VERSION 5.7 ;
  NOWIREEXTENSIONATPIN ON ;
  DIVIDERCHAR "/" ;
  BUSBITCHARS "[]" ;
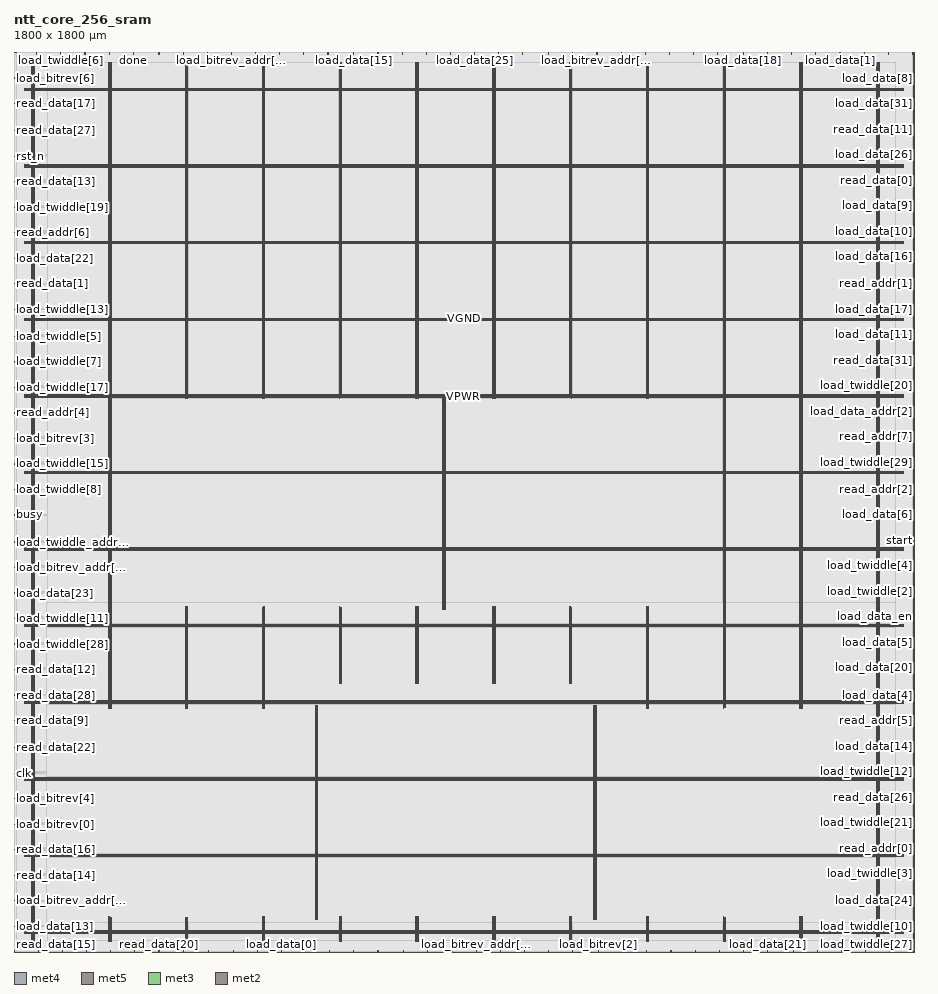
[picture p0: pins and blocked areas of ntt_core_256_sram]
MACRO ntt_core_256_sram
  CLASS BLOCK ;
  FOREIGN ntt_core_256_sram ;
  ORIGIN 0.000 0.000 ;
  SIZE 1800.000 BY 1800.000 ;
  PIN VGND
    DIRECTION INOUT ;
    USE GROUND ;
    PORT
      LAYER met4 ;
        RECT 39.060 21.520 40.660 1779.120 ;
    END
    PORT
      LAYER met4 ;
        RECT 192.660 21.520 194.260 69.400 ;
    END
    PORT
      LAYER met4 ;
        RECT 192.660 487.480 194.260 1779.120 ;
    END
    PORT
      LAYER met4 ;
        RECT 346.260 21.520 347.860 69.400 ;
    END
    PORT
      LAYER met4 ;
        RECT 346.260 487.480 347.860 690.020 ;
    END
    PORT
      LAYER met4 ;
        RECT 346.260 1107.480 347.860 1779.120 ;
    END
    PORT
      LAYER met4 ;
        RECT 499.860 21.520 501.460 70.020 ;
    END
    PORT
      LAYER met4 ;
        RECT 499.860 487.480 501.460 690.020 ;
    END
    PORT
      LAYER met4 ;
        RECT 499.860 1107.480 501.460 1779.120 ;
    END
    PORT
      LAYER met4 ;
        RECT 653.460 21.520 655.060 70.020 ;
    END
    PORT
      LAYER met4 ;
        RECT 653.460 536.440 655.060 689.400 ;
    END
    PORT
      LAYER met4 ;
        RECT 653.460 1108.100 655.060 1779.120 ;
    END
    PORT
      LAYER met4 ;
        RECT 807.060 21.520 808.660 70.020 ;
    END
    PORT
      LAYER met4 ;
        RECT 807.060 536.440 808.660 690.020 ;
    END
    PORT
      LAYER met4 ;
        RECT 807.060 1107.480 808.660 1779.120 ;
    END
    PORT
      LAYER met4 ;
        RECT 960.660 21.520 962.260 70.020 ;
    END
    PORT
      LAYER met4 ;
        RECT 960.660 536.440 962.260 690.020 ;
    END
    PORT
      LAYER met4 ;
        RECT 960.660 1107.480 962.260 1779.120 ;
    END
    PORT
      LAYER met4 ;
        RECT 1114.260 21.520 1115.860 70.020 ;
    END
    PORT
      LAYER met4 ;
        RECT 1114.260 536.440 1115.860 689.400 ;
    END
    PORT
      LAYER met4 ;
        RECT 1114.260 1107.480 1115.860 1779.120 ;
    END
    PORT
      LAYER met4 ;
        RECT 1267.860 21.520 1269.460 70.020 ;
    END
    PORT
      LAYER met4 ;
        RECT 1267.860 487.480 1269.460 690.020 ;
    END
    PORT
      LAYER met4 ;
        RECT 1267.860 1107.480 1269.460 1779.120 ;
    END
    PORT
      LAYER met4 ;
        RECT 1421.460 21.520 1423.060 69.400 ;
    END
    PORT
      LAYER met4 ;
        RECT 1421.460 488.100 1423.060 1779.120 ;
    END
    PORT
      LAYER met4 ;
        RECT 1575.060 21.520 1576.660 70.020 ;
    END
    PORT
      LAYER met4 ;
        RECT 1575.060 487.480 1576.660 1779.120 ;
    END
    PORT
      LAYER met4 ;
        RECT 1728.660 21.520 1730.260 1779.120 ;
    END
    PORT
      LAYER met5 ;
        RECT 20.000 40.910 1779.980 42.510 ;
    END
    PORT
      LAYER met5 ;
        RECT 20.000 194.090 1779.980 195.690 ;
    END
    PORT
      LAYER met5 ;
        RECT 20.000 347.270 1779.980 348.870 ;
    END
    PORT
      LAYER met5 ;
        RECT 20.000 500.450 1779.980 502.050 ;
    END
    PORT
      LAYER met5 ;
        RECT 20.000 653.630 1779.980 655.230 ;
    END
    PORT
      LAYER met5 ;
        RECT 20.000 806.810 1779.980 808.410 ;
    END
    PORT
      LAYER met5 ;
        RECT 20.000 959.990 1779.980 961.590 ;
    END
    PORT
      LAYER met5 ;
        RECT 20.000 1113.170 1779.980 1114.770 ;
    END
    PORT
      LAYER met5 ;
        RECT 20.000 1266.350 1779.980 1267.950 ;
    END
    PORT
      LAYER met5 ;
        RECT 20.000 1419.530 1779.980 1421.130 ;
    END
    PORT
      LAYER met5 ;
        RECT 20.000 1572.710 1779.980 1574.310 ;
    END
    PORT
      LAYER met5 ;
        RECT 20.000 1725.890 1779.980 1727.490 ;
    END
    PORT
      LAYER met4 ;
        RECT 605.940 65.040 607.540 492.560 ;
    END
    PORT
      LAYER met4 ;
        RECT 860.780 685.200 862.380 1112.720 ;
    END
    PORT
      LAYER met4 ;
        RECT 1163.460 65.040 1165.060 492.560 ;
    END
  END VGND
  PIN VPWR
    DIRECTION INOUT ;
    USE POWER ;
    PORT
      LAYER met4 ;
        RECT 35.760 21.520 37.360 1779.120 ;
    END
    PORT
      LAYER met4 ;
        RECT 189.360 21.520 190.960 70.020 ;
    END
    PORT
      LAYER met4 ;
        RECT 189.360 487.480 190.960 1779.120 ;
    END
    PORT
      LAYER met4 ;
        RECT 342.960 21.520 344.560 69.400 ;
    END
    PORT
      LAYER met4 ;
        RECT 342.960 487.480 344.560 690.020 ;
    END
    PORT
      LAYER met4 ;
        RECT 342.960 1107.480 344.560 1779.120 ;
    END
    PORT
      LAYER met4 ;
        RECT 496.560 21.520 498.160 70.020 ;
    END
    PORT
      LAYER met4 ;
        RECT 496.560 487.480 498.160 689.400 ;
    END
    PORT
      LAYER met4 ;
        RECT 496.560 1107.480 498.160 1779.120 ;
    END
    PORT
      LAYER met4 ;
        RECT 650.160 21.520 651.760 70.020 ;
    END
    PORT
      LAYER met4 ;
        RECT 650.160 536.440 651.760 690.020 ;
    END
    PORT
      LAYER met4 ;
        RECT 650.160 1107.480 651.760 1779.120 ;
    END
    PORT
      LAYER met4 ;
        RECT 803.760 21.520 805.360 70.020 ;
    END
    PORT
      LAYER met4 ;
        RECT 803.760 537.060 805.360 690.020 ;
    END
    PORT
      LAYER met4 ;
        RECT 803.760 1107.480 805.360 1779.120 ;
    END
    PORT
      LAYER met4 ;
        RECT 957.360 21.520 958.960 70.020 ;
    END
    PORT
      LAYER met4 ;
        RECT 957.360 536.440 958.960 690.020 ;
    END
    PORT
      LAYER met4 ;
        RECT 957.360 1107.480 958.960 1779.120 ;
    END
    PORT
      LAYER met4 ;
        RECT 1110.960 21.520 1112.560 70.020 ;
    END
    PORT
      LAYER met4 ;
        RECT 1110.960 536.440 1112.560 690.020 ;
    END
    PORT
      LAYER met4 ;
        RECT 1110.960 1108.100 1112.560 1779.120 ;
    END
    PORT
      LAYER met4 ;
        RECT 1264.560 21.520 1266.160 70.020 ;
    END
    PORT
      LAYER met4 ;
        RECT 1264.560 487.480 1266.160 690.020 ;
    END
    PORT
      LAYER met4 ;
        RECT 1264.560 1107.480 1266.160 1779.120 ;
    END
    PORT
      LAYER met4 ;
        RECT 1418.160 21.520 1419.760 70.020 ;
    END
    PORT
      LAYER met4 ;
        RECT 1418.160 487.480 1419.760 1779.120 ;
    END
    PORT
      LAYER met4 ;
        RECT 1571.760 21.520 1573.360 70.020 ;
    END
    PORT
      LAYER met4 ;
        RECT 1571.760 487.480 1573.360 1779.120 ;
    END
    PORT
      LAYER met4 ;
        RECT 1725.360 21.520 1726.960 1779.120 ;
    END
    PORT
      LAYER met5 ;
        RECT 20.000 37.610 1779.980 39.210 ;
    END
    PORT
      LAYER met5 ;
        RECT 20.000 190.790 1779.980 192.390 ;
    END
    PORT
      LAYER met5 ;
        RECT 20.000 343.970 1779.980 345.570 ;
    END
    PORT
      LAYER met5 ;
        RECT 20.000 497.150 1779.980 498.750 ;
    END
    PORT
      LAYER met5 ;
        RECT 20.000 650.330 1779.980 651.930 ;
    END
    PORT
      LAYER met5 ;
        RECT 20.000 803.510 1779.980 805.110 ;
    END
    PORT
      LAYER met5 ;
        RECT 20.000 956.690 1779.980 958.290 ;
    END
    PORT
      LAYER met5 ;
        RECT 20.000 1109.870 1779.980 1111.470 ;
    END
    PORT
      LAYER met5 ;
        RECT 20.000 1263.050 1779.980 1264.650 ;
    END
    PORT
      LAYER met5 ;
        RECT 20.000 1416.230 1779.980 1417.830 ;
    END
    PORT
      LAYER met5 ;
        RECT 20.000 1569.410 1779.980 1571.010 ;
    END
    PORT
      LAYER met5 ;
        RECT 20.000 1722.590 1779.980 1724.190 ;
    END
    PORT
      LAYER met4 ;
        RECT 602.260 65.040 603.860 492.560 ;
    END
    PORT
      LAYER met4 ;
        RECT 857.100 685.200 858.700 1112.720 ;
    END
    PORT
      LAYER met4 ;
        RECT 1159.780 65.040 1161.380 492.560 ;
    END
  END VPWR
  PIN busy
    DIRECTION OUTPUT TRISTATE ;
    USE SIGNAL ;
    ANTENNADIFFAREA 0.795200 ;
    PORT
      LAYER met3 ;
        RECT 0.000 873.840 4.000 874.440 ;
    END
  END busy
  PIN clk
    DIRECTION INPUT ;
    USE SIGNAL ;
    ANTENNAGATEAREA 4.764300 ;
    ANTENNADIFFAREA 3.912300 ;
    PORT
      LAYER met3 ;
        RECT 0.000 357.040 4.000 357.640 ;
    END
  END clk
  PIN done
    DIRECTION OUTPUT TRISTATE ;
    USE SIGNAL ;
    ANTENNADIFFAREA 0.795200 ;
    PORT
      LAYER met2 ;
        RECT 238.370 1796.000 238.650 1800.000 ;
    END
  END done
  PIN load_bitrev[0]
    DIRECTION INPUT ;
    USE SIGNAL ;
    ANTENNAGATEAREA 0.929700 ;
    ANTENNADIFFAREA 0.434700 ;
    PORT
      LAYER met3 ;
        RECT 0.000 255.040 4.000 255.640 ;
    END
  END load_bitrev[0]
  PIN load_bitrev[1]
    DIRECTION INPUT ;
    USE SIGNAL ;
    ANTENNAGATEAREA 0.631200 ;
    ANTENNADIFFAREA 0.434700 ;
    PORT
      LAYER met2 ;
        RECT 1606.870 0.000 1607.150 4.000 ;
    END
  END load_bitrev[1]
  PIN load_bitrev[2]
    DIRECTION INPUT ;
    USE SIGNAL ;
    ANTENNAGATEAREA 0.647700 ;
    ANTENNADIFFAREA 0.434700 ;
    PORT
      LAYER met2 ;
        RECT 1168.950 0.000 1169.230 4.000 ;
    END
  END load_bitrev[2]
  PIN load_bitrev[3]
    DIRECTION INPUT ;
    USE SIGNAL ;
    ANTENNAGATEAREA 0.852000 ;
    PORT
      LAYER met3 ;
        RECT 0.000 1026.840 4.000 1027.440 ;
    END
  END load_bitrev[3]
  PIN load_bitrev[4]
    DIRECTION INPUT ;
    USE SIGNAL ;
    ANTENNAGATEAREA 0.929700 ;
    ANTENNADIFFAREA 0.434700 ;
    PORT
      LAYER met3 ;
        RECT 0.000 306.040 4.000 306.640 ;
    END
  END load_bitrev[4]
  PIN load_bitrev[5]
    DIRECTION INPUT ;
    USE SIGNAL ;
    ANTENNAGATEAREA 0.990000 ;
    PORT
      LAYER met2 ;
        RECT 824.410 1796.000 824.690 1800.000 ;
    END
  END load_bitrev[5]
  PIN load_bitrev[6]
    DIRECTION INPUT ;
    USE SIGNAL ;
    ANTENNAGATEAREA 0.990000 ;
    PORT
      LAYER met3 ;
        RECT 0.000 1747.640 4.000 1748.240 ;
    END
  END load_bitrev[6]
  PIN load_bitrev[7]
    DIRECTION INPUT ;
    USE SIGNAL ;
    ANTENNAGATEAREA 0.631200 ;
    ANTENNADIFFAREA 0.434700 ;
    PORT
      LAYER met2 ;
        RECT 582.910 0.000 583.190 4.000 ;
    END
  END load_bitrev[7]
  PIN load_bitrev_addr[0]
    DIRECTION INPUT ;
    USE SIGNAL ;
    ANTENNAGATEAREA 0.682200 ;
    ANTENNADIFFAREA 0.434700 ;
    PORT
      LAYER met2 ;
        RECT 1313.850 0.000 1314.130 4.000 ;
    END
  END load_bitrev_addr[0]
  PIN load_bitrev_addr[1]
    DIRECTION INPUT ;
    USE SIGNAL ;
    ANTENNAGATEAREA 0.990000 ;
    PORT
      LAYER met2 ;
        RECT 1165.730 1796.000 1166.010 1800.000 ;
    END
  END load_bitrev_addr[1]
  PIN load_bitrev_addr[2]
    DIRECTION INPUT ;
    USE SIGNAL ;
    ANTENNAGATEAREA 0.852000 ;
    PORT
      LAYER met2 ;
        RECT 289.890 1796.000 290.170 1800.000 ;
    END
  END load_bitrev_addr[2]
  PIN load_bitrev_addr[3]
    DIRECTION INPUT ;
    USE SIGNAL ;
    ANTENNAGATEAREA 0.682200 ;
    ANTENNADIFFAREA 0.434700 ;
    PORT
      LAYER met2 ;
        RECT 1117.430 0.000 1117.710 4.000 ;
    END
  END load_bitrev_addr[3]
  PIN load_bitrev_addr[4]
    DIRECTION INPUT ;
    USE SIGNAL ;
    ANTENNAGATEAREA 0.990000 ;
    PORT
      LAYER met2 ;
        RECT 434.790 1796.000 435.070 1800.000 ;
    END
  END load_bitrev_addr[4]
  PIN load_bitrev_addr[5]
    DIRECTION INPUT ;
    USE SIGNAL ;
    ANTENNAGATEAREA 0.647700 ;
    ANTENNADIFFAREA 0.434700 ;
    PORT
      LAYER met2 ;
        RECT 924.230 0.000 924.510 4.000 ;
    END
  END load_bitrev_addr[5]
  PIN load_bitrev_addr[6]
    DIRECTION INPUT ;
    USE SIGNAL ;
    ANTENNAGATEAREA 0.860700 ;
    ANTENNADIFFAREA 0.434700 ;
    PORT
      LAYER met3 ;
        RECT 0.000 768.440 4.000 769.040 ;
    END
  END load_bitrev_addr[6]
  PIN load_bitrev_addr[7]
    DIRECTION INPUT ;
    USE SIGNAL ;
    ANTENNAGATEAREA 0.860700 ;
    ANTENNADIFFAREA 0.434700 ;
    PORT
      LAYER met3 ;
        RECT 0.000 102.040 4.000 102.640 ;
    END
  END load_bitrev_addr[7]
  PIN load_bitrev_en
    DIRECTION INPUT ;
    USE SIGNAL ;
    ANTENNAGATEAREA 0.990000 ;
    PORT
      LAYER met2 ;
        RECT 1262.330 1796.000 1262.610 1800.000 ;
    END
  END load_bitrev_en
  PIN load_data[0]
    DIRECTION INPUT ;
    USE SIGNAL ;
    ANTENNAGATEAREA 0.631200 ;
    ANTENNADIFFAREA 0.434700 ;
    PORT
      LAYER met2 ;
        RECT 534.610 0.000 534.890 4.000 ;
    END
  END load_data[0]
  PIN load_data[10]
    DIRECTION INPUT ;
    USE SIGNAL ;
    ANTENNAGATEAREA 1.177200 ;
    ANTENNADIFFAREA 0.434700 ;
    PORT
      LAYER met3 ;
        RECT 1796.000 1441.640 1800.000 1442.240 ;
    END
  END load_data[10]
  PIN load_data[11]
    DIRECTION INPUT ;
    USE SIGNAL ;
    ANTENNAGATEAREA 1.424700 ;
    ANTENNADIFFAREA 0.434700 ;
    PORT
      LAYER met3 ;
        RECT 1796.000 1234.240 1800.000 1234.840 ;
    END
  END load_data[11]
  PIN load_data[12]
    DIRECTION INPUT ;
    USE SIGNAL ;
    ANTENNAGATEAREA 0.560700 ;
    ANTENNADIFFAREA 0.434700 ;
    PORT
      LAYER met2 ;
        RECT 438.010 0.000 438.290 4.000 ;
    END
  END load_data[12]
  PIN load_data[13]
    DIRECTION INPUT ;
    USE SIGNAL ;
    ANTENNAGATEAREA 0.647700 ;
    ANTENNADIFFAREA 0.434700 ;
    PORT
      LAYER met3 ;
        RECT 0.000 51.040 4.000 51.640 ;
    END
  END load_data[13]
  PIN load_data[14]
    DIRECTION INPUT ;
    USE SIGNAL ;
    ANTENNAGATEAREA 0.990000 ;
    PORT
      LAYER met3 ;
        RECT 1796.000 411.440 1800.000 412.040 ;
    END
  END load_data[14]
  PIN load_data[15]
    DIRECTION INPUT ;
    USE SIGNAL ;
    ANTENNAGATEAREA 0.990000 ;
    PORT
      LAYER met2 ;
        RECT 679.510 1796.000 679.790 1800.000 ;
    END
  END load_data[15]
  PIN load_data[16]
    DIRECTION INPUT ;
    USE SIGNAL ;
    ANTENNAGATEAREA 0.990000 ;
    PORT
      LAYER met3 ;
        RECT 1796.000 1390.640 1800.000 1391.240 ;
    END
  END load_data[16]
  PIN load_data[17]
    DIRECTION INPUT ;
    USE SIGNAL ;
    ANTENNAGATEAREA 0.990000 ;
    PORT
      LAYER met3 ;
        RECT 1796.000 1285.240 1800.000 1285.840 ;
    END
  END load_data[17]
  PIN load_data[18]
    DIRECTION INPUT ;
    USE SIGNAL ;
    ANTENNAGATEAREA 0.990000 ;
    PORT
      LAYER met2 ;
        RECT 1458.750 1796.000 1459.030 1800.000 ;
    END
  END load_data[18]
  PIN load_data[19]
    DIRECTION INPUT ;
    USE SIGNAL ;
    ANTENNAGATEAREA 0.647700 ;
    ANTENNADIFFAREA 0.434700 ;
    PORT
      LAYER met2 ;
        RECT 827.630 0.000 827.910 4.000 ;
    END
  END load_data[19]
  PIN load_data[1]
    DIRECTION INPUT ;
    USE SIGNAL ;
    ANTENNAGATEAREA 0.990000 ;
    PORT
      LAYER met2 ;
        RECT 1651.950 1796.000 1652.230 1800.000 ;
    END
  END load_data[1]
  PIN load_data[20]
    DIRECTION INPUT ;
    USE SIGNAL ;
    ANTENNAGATEAREA 0.990000 ;
    PORT
      LAYER met3 ;
        RECT 1796.000 567.840 1800.000 568.440 ;
    END
  END load_data[20]
  PIN load_data[21]
    DIRECTION INPUT ;
    USE SIGNAL ;
    ANTENNAGATEAREA 0.742500 ;
    PORT
      LAYER met2 ;
        RECT 1507.050 0.000 1507.330 4.000 ;
    END
  END load_data[21]
  PIN load_data[22]
    DIRECTION INPUT ;
    USE SIGNAL ;
    ANTENNAGATEAREA 0.852000 ;
    PORT
      LAYER met3 ;
        RECT 0.000 1387.240 4.000 1387.840 ;
    END
  END load_data[22]
  PIN load_data[23]
    DIRECTION INPUT ;
    USE SIGNAL ;
    ANTENNAGATEAREA 0.860700 ;
    ANTENNADIFFAREA 0.434700 ;
    PORT
      LAYER met3 ;
        RECT 0.000 717.440 4.000 718.040 ;
    END
  END load_data[23]
  PIN load_data[24]
    DIRECTION INPUT ;
    USE SIGNAL ;
    ANTENNAGATEAREA 0.742500 ;
    PORT
      LAYER met3 ;
        RECT 1796.000 102.040 1800.000 102.640 ;
    END
  END load_data[24]
  PIN load_data[25]
    DIRECTION INPUT ;
    USE SIGNAL ;
    ANTENNAGATEAREA 0.990000 ;
    PORT
      LAYER met2 ;
        RECT 921.010 1796.000 921.290 1800.000 ;
    END
  END load_data[25]
  PIN load_data[26]
    DIRECTION INPUT ;
    USE SIGNAL ;
    ANTENNAGATEAREA 1.424700 ;
    ANTENNADIFFAREA 0.434700 ;
    PORT
      LAYER met3 ;
        RECT 1796.000 1594.640 1800.000 1595.240 ;
    END
  END load_data[26]
  PIN load_data[27]
    DIRECTION INPUT ;
    USE SIGNAL ;
    ANTENNAGATEAREA 1.177200 ;
    ANTENNADIFFAREA 0.434700 ;
    PORT
      LAYER met3 ;
        RECT 1796.000 0.040 1800.000 0.640 ;
    END
  END load_data[27]
  PIN load_data[28]
    DIRECTION INPUT ;
    USE SIGNAL ;
    ANTENNAGATEAREA 0.990000 ;
    PORT
      LAYER met2 ;
        RECT 872.710 1796.000 872.990 1800.000 ;
    END
  END load_data[28]
  PIN load_data[29]
    DIRECTION INPUT ;
    USE SIGNAL ;
    ANTENNAGATEAREA 0.860700 ;
    ANTENNADIFFAREA 0.434700 ;
    PORT
      LAYER met2 ;
        RECT 1558.570 0.000 1558.850 4.000 ;
    END
  END load_data[29]
  PIN load_data[2]
    DIRECTION INPUT ;
    USE SIGNAL ;
    ANTENNAGATEAREA 0.990000 ;
    PORT
      LAYER met2 ;
        RECT 1407.230 1796.000 1407.510 1800.000 ;
    END
  END load_data[2]
  PIN load_data[30]
    DIRECTION INPUT ;
    USE SIGNAL ;
    ANTENNAGATEAREA 0.990000 ;
    PORT
      LAYER met2 ;
        RECT 1555.350 1796.000 1555.630 1800.000 ;
    END
  END load_data[30]
  PIN load_data[31]
    DIRECTION INPUT ;
    USE SIGNAL ;
    ANTENNAGATEAREA 1.424700 ;
    ANTENNADIFFAREA 0.434700 ;
    PORT
      LAYER met3 ;
        RECT 1796.000 1696.640 1800.000 1697.240 ;
    END
  END load_data[31]
  PIN load_data[3]
    DIRECTION INPUT ;
    USE SIGNAL ;
    ANTENNAGATEAREA 0.990000 ;
    PORT
      LAYER met2 ;
        RECT 727.810 1796.000 728.090 1800.000 ;
    END
  END load_data[3]
  PIN load_data[4]
    DIRECTION INPUT ;
    USE SIGNAL ;
    ANTENNAGATEAREA 0.990000 ;
    PORT
      LAYER met3 ;
        RECT 1796.000 513.440 1800.000 514.040 ;
    END
  END load_data[4]
  PIN load_data[5]
    DIRECTION INPUT ;
    USE SIGNAL ;
    ANTENNAGATEAREA 0.990000 ;
    PORT
      LAYER met3 ;
        RECT 1796.000 618.840 1800.000 619.440 ;
    END
  END load_data[5]
  PIN load_data[6]
    DIRECTION INPUT ;
    USE SIGNAL ;
    ANTENNAGATEAREA 0.990000 ;
    PORT
      LAYER met3 ;
        RECT 1796.000 873.840 1800.000 874.440 ;
    END
  END load_data[6]
  PIN load_data[7]
    DIRECTION INPUT ;
    USE SIGNAL ;
    ANTENNAGATEAREA 0.742500 ;
    PORT
      LAYER met2 ;
        RECT 1265.550 0.000 1265.830 4.000 ;
    END
  END load_data[7]
  PIN load_data[8]
    DIRECTION INPUT ;
    USE SIGNAL ;
    ANTENNAGATEAREA 0.990000 ;
    PORT
      LAYER met3 ;
        RECT 1796.000 1747.640 1800.000 1748.240 ;
    END
  END load_data[8]
  PIN load_data[9]
    DIRECTION INPUT ;
    USE SIGNAL ;
    ANTENNAGATEAREA 0.990000 ;
    PORT
      LAYER met3 ;
        RECT 1796.000 1492.640 1800.000 1493.240 ;
    END
  END load_data[9]
  PIN load_data_addr[0]
    DIRECTION INPUT ;
    USE SIGNAL ;
    ANTENNAGATEAREA 0.990000 ;
    PORT
      LAYER met2 ;
        RECT 1117.430 1796.000 1117.710 1800.000 ;
    END
  END load_data_addr[0]
  PIN load_data_addr[1]
    DIRECTION INPUT ;
    USE SIGNAL ;
    ANTENNAGATEAREA 0.990000 ;
    PORT
      LAYER met2 ;
        RECT 579.690 1796.000 579.970 1800.000 ;
    END
  END load_data_addr[1]
  PIN load_data_addr[2]
    DIRECTION INPUT ;
    USE SIGNAL ;
    ANTENNAGATEAREA 0.990000 ;
    PORT
      LAYER met3 ;
        RECT 1796.000 1081.240 1800.000 1081.840 ;
    END
  END load_data_addr[2]
  PIN load_data_addr[3]
    DIRECTION INPUT ;
    USE SIGNAL ;
    ANTENNAGATEAREA 0.990000 ;
    PORT
      LAYER met2 ;
        RECT 386.490 1796.000 386.770 1800.000 ;
    END
  END load_data_addr[3]
  PIN load_data_addr[4]
    DIRECTION INPUT ;
    USE SIGNAL ;
    ANTENNAGATEAREA 0.990000 ;
    PORT
      LAYER met2 ;
        RECT 531.390 1796.000 531.670 1800.000 ;
    END
  END load_data_addr[4]
  PIN load_data_addr[5]
    DIRECTION INPUT ;
    USE SIGNAL ;
    ANTENNAGATEAREA 0.990000 ;
    PORT
      LAYER met2 ;
        RECT 1017.610 1796.000 1017.890 1800.000 ;
    END
  END load_data_addr[5]
  PIN load_data_addr[6]
    DIRECTION INPUT ;
    USE SIGNAL ;
    ANTENNAGATEAREA 0.631200 ;
    ANTENNADIFFAREA 0.434700 ;
    PORT
      LAYER met2 ;
        RECT 486.310 0.000 486.590 4.000 ;
    END
  END load_data_addr[6]
  PIN load_data_addr[7]
    DIRECTION INPUT ;
    USE SIGNAL ;
    ANTENNAGATEAREA 0.852000 ;
    PORT
      LAYER met2 ;
        RECT 141.770 1796.000 142.050 1800.000 ;
    END
  END load_data_addr[7]
  PIN load_data_en
    DIRECTION INPUT ;
    USE SIGNAL ;
    ANTENNAGATEAREA 1.424700 ;
    ANTENNADIFFAREA 0.434700 ;
    PORT
      LAYER met3 ;
        RECT 1796.000 669.840 1800.000 670.440 ;
    END
  END load_data_en
  PIN load_twiddle[0]
    DIRECTION INPUT ;
    USE SIGNAL ;
    ANTENNAGATEAREA 0.990000 ;
    PORT
      LAYER met2 ;
        RECT 190.070 1796.000 190.350 1800.000 ;
    END
  END load_twiddle[0]
  PIN load_twiddle[10]
    DIRECTION INPUT ;
    USE SIGNAL ;
    ANTENNAGATEAREA 0.159000 ;
    PORT
      LAYER met3 ;
        RECT 1796.000 51.040 1800.000 51.640 ;
    END
  END load_twiddle[10]
  PIN load_twiddle[11]
    DIRECTION INPUT ;
    USE SIGNAL ;
    ANTENNAGATEAREA 0.990000 ;
    PORT
      LAYER met3 ;
        RECT 0.000 666.440 4.000 667.040 ;
    END
  END load_twiddle[11]
  PIN load_twiddle[12]
    DIRECTION INPUT ;
    USE SIGNAL ;
    ANTENNAGATEAREA 0.247500 ;
    PORT
      LAYER met3 ;
        RECT 1796.000 360.440 1800.000 361.040 ;
    END
  END load_twiddle[12]
  PIN load_twiddle[13]
    DIRECTION INPUT ;
    USE SIGNAL ;
    ANTENNAGATEAREA 0.990000 ;
    PORT
      LAYER met3 ;
        RECT 0.000 1285.240 4.000 1285.840 ;
    END
  END load_twiddle[13]
  PIN load_twiddle[14]
    DIRECTION INPUT ;
    USE SIGNAL ;
    ANTENNAGATEAREA 0.682200 ;
    ANTENNADIFFAREA 0.434700 ;
    PORT
      LAYER met2 ;
        RECT 779.330 0.000 779.610 4.000 ;
    END
  END load_twiddle[14]
  PIN load_twiddle[15]
    DIRECTION INPUT ;
    USE SIGNAL ;
    ANTENNAGATEAREA 0.990000 ;
    PORT
      LAYER met3 ;
        RECT 0.000 975.840 4.000 976.440 ;
    END
  END load_twiddle[15]
  PIN load_twiddle[16]
    DIRECTION INPUT ;
    USE SIGNAL ;
    ANTENNAGATEAREA 0.682200 ;
    ANTENNADIFFAREA 0.434700 ;
    PORT
      LAYER met2 ;
        RECT 727.810 0.000 728.090 4.000 ;
    END
  END load_twiddle[16]
  PIN load_twiddle[17]
    DIRECTION INPUT ;
    USE SIGNAL ;
    ANTENNAGATEAREA 0.990000 ;
    PORT
      LAYER met3 ;
        RECT 0.000 1128.840 4.000 1129.440 ;
    END
  END load_twiddle[17]
  PIN load_twiddle[18]
    DIRECTION INPUT ;
    USE SIGNAL ;
    ANTENNAGATEAREA 0.990000 ;
    PORT
      LAYER met2 ;
        RECT 1507.050 1796.000 1507.330 1800.000 ;
    END
  END load_twiddle[18]
  PIN load_twiddle[19]
    DIRECTION INPUT ;
    USE SIGNAL ;
    ANTENNAGATEAREA 0.990000 ;
    PORT
      LAYER met3 ;
        RECT 0.000 1489.240 4.000 1489.840 ;
    END
  END load_twiddle[19]
  PIN load_twiddle[1]
    DIRECTION INPUT ;
    USE SIGNAL ;
    ANTENNAGATEAREA 0.631200 ;
    ANTENNADIFFAREA 0.434700 ;
    PORT
      LAYER met2 ;
        RECT 1362.150 0.000 1362.430 4.000 ;
    END
  END load_twiddle[1]
  PIN load_twiddle[20]
    DIRECTION INPUT ;
    USE SIGNAL ;
    ANTENNAGATEAREA 0.742500 ;
    PORT
      LAYER met3 ;
        RECT 1796.000 1132.240 1800.000 1132.840 ;
    END
  END load_twiddle[20]
  PIN load_twiddle[21]
    DIRECTION INPUT ;
    USE SIGNAL ;
    ANTENNAGATEAREA 0.213000 ;
    PORT
      LAYER met3 ;
        RECT 1796.000 258.440 1800.000 259.040 ;
    END
  END load_twiddle[21]
  PIN load_twiddle[22]
    DIRECTION INPUT ;
    USE SIGNAL ;
    ANTENNAGATEAREA 0.990000 ;
    PORT
      LAYER met2 ;
        RECT 1214.030 1796.000 1214.310 1800.000 ;
    END
  END load_twiddle[22]
  PIN load_twiddle[23]
    DIRECTION INPUT ;
    USE SIGNAL ;
    ANTENNAGATEAREA 0.990000 ;
    PORT
      LAYER met2 ;
        RECT 1796.850 1796.000 1797.130 1800.000 ;
    END
  END load_twiddle[23]
  PIN load_twiddle[24]
    DIRECTION INPUT ;
    USE SIGNAL ;
    ANTENNAGATEAREA 0.990000 ;
    PORT
      LAYER met2 ;
        RECT 1700.250 1796.000 1700.530 1800.000 ;
    END
  END load_twiddle[24]
  PIN load_twiddle[25]
    DIRECTION INPUT ;
    USE SIGNAL ;
    ANTENNAGATEAREA 0.990000 ;
    PORT
      LAYER met2 ;
        RECT 48.390 0.000 48.670 4.000 ;
    END
  END load_twiddle[25]
  PIN load_twiddle[26]
    DIRECTION INPUT ;
    USE SIGNAL ;
    ANTENNAGATEAREA 0.742500 ;
    PORT
      LAYER met2 ;
        RECT 241.590 0.000 241.870 4.000 ;
    END
  END load_twiddle[26]
  PIN load_twiddle[27]
    DIRECTION INPUT ;
    USE SIGNAL ;
    ANTENNAGATEAREA 0.647700 ;
    ANTENNADIFFAREA 0.434700 ;
    PORT
      LAYER met2 ;
        RECT 1751.770 0.000 1752.050 4.000 ;
    END
  END load_twiddle[27]
  PIN load_twiddle[28]
    DIRECTION INPUT ;
    USE SIGNAL ;
    ANTENNAGATEAREA 0.990000 ;
    PORT
      LAYER met3 ;
        RECT 0.000 615.440 4.000 616.040 ;
    END
  END load_twiddle[28]
  PIN load_twiddle[29]
    DIRECTION INPUT ;
    USE SIGNAL ;
    ANTENNAGATEAREA 1.177200 ;
    ANTENNADIFFAREA 0.434700 ;
    PORT
      LAYER met3 ;
        RECT 1796.000 979.240 1800.000 979.840 ;
    END
  END load_twiddle[29]
  PIN load_twiddle[2]
    DIRECTION INPUT ;
    USE SIGNAL ;
    ANTENNAGATEAREA 0.742500 ;
    PORT
      LAYER met3 ;
        RECT 1796.000 720.840 1800.000 721.440 ;
    END
  END load_twiddle[2]
  PIN load_twiddle[30]
    DIRECTION INPUT ;
    USE SIGNAL ;
    ANTENNAGATEAREA 0.990000 ;
    PORT
      LAYER met2 ;
        RECT 776.110 1796.000 776.390 1800.000 ;
    END
  END load_twiddle[30]
  PIN load_twiddle[31]
    DIRECTION INPUT ;
    USE SIGNAL ;
    ANTENNAGATEAREA 0.852000 ;
    PORT
      LAYER met2 ;
        RECT 144.990 0.000 145.270 4.000 ;
    END
  END load_twiddle[31]
  PIN load_twiddle[3]
    DIRECTION INPUT ;
    USE SIGNAL ;
    ANTENNAGATEAREA 0.647700 ;
    ANTENNADIFFAREA 0.434700 ;
    PORT
      LAYER met3 ;
        RECT 1796.000 156.440 1800.000 157.040 ;
    END
  END load_twiddle[3]
  PIN load_twiddle[4]
    DIRECTION INPUT ;
    USE SIGNAL ;
    ANTENNAGATEAREA 1.177200 ;
    ANTENNADIFFAREA 0.434700 ;
    PORT
      LAYER met3 ;
        RECT 1796.000 771.840 1800.000 772.440 ;
    END
  END load_twiddle[4]
  PIN load_twiddle[5]
    DIRECTION INPUT ;
    USE SIGNAL ;
    ANTENNAGATEAREA 0.990000 ;
    PORT
      LAYER met3 ;
        RECT 0.000 1230.840 4.000 1231.440 ;
    END
  END load_twiddle[5]
  PIN load_twiddle[6]
    DIRECTION INPUT ;
    USE SIGNAL ;
    ANTENNAGATEAREA 0.990000 ;
    PORT
      LAYER met2 ;
        RECT 93.470 1796.000 93.750 1800.000 ;
    END
  END load_twiddle[6]
  PIN load_twiddle[7]
    DIRECTION INPUT ;
    USE SIGNAL ;
    ANTENNAGATEAREA 0.990000 ;
    PORT
      LAYER met3 ;
        RECT 0.000 1179.840 4.000 1180.440 ;
    END
  END load_twiddle[7]
  PIN load_twiddle[8]
    DIRECTION INPUT ;
    USE SIGNAL ;
    ANTENNAGATEAREA 0.990000 ;
    PORT
      LAYER met3 ;
        RECT 0.000 924.840 4.000 925.440 ;
    END
  END load_twiddle[8]
  PIN load_twiddle[9]
    DIRECTION INPUT ;
    USE SIGNAL ;
    ANTENNAGATEAREA 1.424700 ;
    ANTENNADIFFAREA 0.434700 ;
    PORT
      LAYER met3 ;
        RECT 0.000 1798.640 4.000 1799.240 ;
    END
  END load_twiddle[9]
  PIN load_twiddle_addr[0]
    DIRECTION INPUT ;
    USE SIGNAL ;
    ANTENNAGATEAREA 0.990000 ;
    PORT
      LAYER met2 ;
        RECT 1748.550 1796.000 1748.830 1800.000 ;
    END
  END load_twiddle_addr[0]
  PIN load_twiddle_addr[1]
    DIRECTION INPUT ;
    USE SIGNAL ;
    ANTENNAGATEAREA 0.647700 ;
    ANTENNADIFFAREA 0.434700 ;
    PORT
      LAYER met2 ;
        RECT 389.710 0.000 389.990 4.000 ;
    END
  END load_twiddle_addr[1]
  PIN load_twiddle_addr[2]
    DIRECTION INPUT ;
    USE SIGNAL ;
    ANTENNAGATEAREA 1.177200 ;
    ANTENNADIFFAREA 0.434700 ;
    PORT
      LAYER met3 ;
        RECT 0.000 819.440 4.000 820.040 ;
    END
  END load_twiddle_addr[2]
  PIN load_twiddle_addr[3]
    DIRECTION INPUT ;
    USE SIGNAL ;
    ANTENNAGATEAREA 0.647700 ;
    ANTENNADIFFAREA 0.434700 ;
    PORT
      LAYER met2 ;
        RECT 1069.130 0.000 1069.410 4.000 ;
    END
  END load_twiddle_addr[3]
  PIN load_twiddle_addr[4]
    DIRECTION INPUT ;
    USE SIGNAL ;
    ANTENNAGATEAREA 0.682200 ;
    ANTENNADIFFAREA 0.434700 ;
    PORT
      LAYER met2 ;
        RECT 1703.470 0.000 1703.750 4.000 ;
    END
  END load_twiddle_addr[4]
  PIN load_twiddle_addr[5]
    DIRECTION INPUT ;
    USE SIGNAL ;
    ANTENNAGATEAREA 0.852000 ;
    PORT
      LAYER met2 ;
        RECT 627.990 1796.000 628.270 1800.000 ;
    END
  END load_twiddle_addr[5]
  PIN load_twiddle_addr[6]
    DIRECTION INPUT ;
    USE SIGNAL ;
    ANTENNAGATEAREA 0.647700 ;
    ANTENNADIFFAREA 0.434700 ;
    PORT
      LAYER met2 ;
        RECT 1410.450 0.000 1410.730 4.000 ;
    END
  END load_twiddle_addr[6]
  PIN load_twiddle_addr[7]
    DIRECTION INPUT ;
    USE SIGNAL ;
    ANTENNAGATEAREA 0.682200 ;
    ANTENNADIFFAREA 0.434700 ;
    PORT
      LAYER met2 ;
        RECT 193.290 0.000 193.570 4.000 ;
    END
  END load_twiddle_addr[7]
  PIN load_twiddle_en
    DIRECTION INPUT ;
    USE SIGNAL ;
    ANTENNAGATEAREA 0.682200 ;
    ANTENNADIFFAREA 0.434700 ;
    PORT
      LAYER met2 ;
        RECT 679.510 0.000 679.790 4.000 ;
    END
  END load_twiddle_en
  PIN read_addr[0]
    DIRECTION INPUT ;
    USE SIGNAL ;
    ANTENNAGATEAREA 1.286700 ;
    ANTENNADIFFAREA 0.434700 ;
    PORT
      LAYER met3 ;
        RECT 1796.000 207.440 1800.000 208.040 ;
    END
  END read_addr[0]
  PIN read_addr[1]
    DIRECTION INPUT ;
    USE SIGNAL ;
    ANTENNAGATEAREA 0.990000 ;
    PORT
      LAYER met3 ;
        RECT 1796.000 1336.240 1800.000 1336.840 ;
    END
  END read_addr[1]
  PIN read_addr[2]
    DIRECTION INPUT ;
    USE SIGNAL ;
    ANTENNAGATEAREA 1.286700 ;
    ANTENNADIFFAREA 0.434700 ;
    PORT
      LAYER met3 ;
        RECT 1796.000 924.840 1800.000 925.440 ;
    END
  END read_addr[2]
  PIN read_addr[3]
    DIRECTION INPUT ;
    USE SIGNAL ;
    ANTENNAGATEAREA 0.852000 ;
    PORT
      LAYER met2 ;
        RECT 1458.750 0.000 1459.030 4.000 ;
    END
  END read_addr[3]
  PIN read_addr[4]
    DIRECTION INPUT ;
    USE SIGNAL ;
    ANTENNAGATEAREA 1.177200 ;
    ANTENNADIFFAREA 0.434700 ;
    PORT
      LAYER met3 ;
        RECT 0.000 1077.840 4.000 1078.440 ;
    END
  END read_addr[4]
  PIN read_addr[5]
    DIRECTION INPUT ;
    USE SIGNAL ;
    ANTENNAGATEAREA 1.286700 ;
    ANTENNADIFFAREA 0.434700 ;
    PORT
      LAYER met3 ;
        RECT 1796.000 462.440 1800.000 463.040 ;
    END
  END read_addr[5]
  PIN read_addr[6]
    DIRECTION INPUT ;
    USE SIGNAL ;
    ANTENNAGATEAREA 0.990000 ;
    PORT
      LAYER met3 ;
        RECT 0.000 1438.240 4.000 1438.840 ;
    END
  END read_addr[6]
  PIN read_addr[7]
    DIRECTION INPUT ;
    USE SIGNAL ;
    ANTENNAGATEAREA 1.286700 ;
    ANTENNADIFFAREA 0.434700 ;
    PORT
      LAYER met3 ;
        RECT 1796.000 1030.240 1800.000 1030.840 ;
    END
  END read_addr[7]
  PIN read_data[0]
    DIRECTION OUTPUT TRISTATE ;
    USE SIGNAL ;
    ANTENNADIFFAREA 0.795200 ;
    PORT
      LAYER met3 ;
        RECT 1796.000 1543.640 1800.000 1544.240 ;
    END
  END read_data[0]
  PIN read_data[10]
    DIRECTION OUTPUT TRISTATE ;
    USE SIGNAL ;
    ANTENNADIFFAREA 0.795200 ;
    PORT
      LAYER met2 ;
        RECT 1655.170 0.000 1655.450 4.000 ;
    END
  END read_data[10]
  PIN read_data[11]
    DIRECTION OUTPUT TRISTATE ;
    USE SIGNAL ;
    ANTENNADIFFAREA 0.795200 ;
    PORT
      LAYER met3 ;
        RECT 1796.000 1645.640 1800.000 1646.240 ;
    END
  END read_data[11]
  PIN read_data[12]
    DIRECTION OUTPUT TRISTATE ;
    USE SIGNAL ;
    ANTENNADIFFAREA 0.795200 ;
    PORT
      LAYER met3 ;
        RECT 0.000 564.440 4.000 565.040 ;
    END
  END read_data[12]
  PIN read_data[13]
    DIRECTION OUTPUT TRISTATE ;
    USE SIGNAL ;
    ANTENNADIFFAREA 0.795200 ;
    PORT
      LAYER met3 ;
        RECT 0.000 1540.240 4.000 1540.840 ;
    END
  END read_data[13]
  PIN read_data[14]
    DIRECTION OUTPUT TRISTATE ;
    USE SIGNAL ;
    ANTENNADIFFAREA 0.795200 ;
    PORT
      LAYER met3 ;
        RECT 0.000 153.040 4.000 153.640 ;
    END
  END read_data[14]
  PIN read_data[15]
    DIRECTION OUTPUT TRISTATE ;
    USE SIGNAL ;
    ANTENNADIFFAREA 0.795200 ;
    PORT
      LAYER met2 ;
        RECT 0.090 0.000 0.370 4.000 ;
    END
  END read_data[15]
  PIN read_data[16]
    DIRECTION OUTPUT TRISTATE ;
    USE SIGNAL ;
    ANTENNADIFFAREA 0.795200 ;
    PORT
      LAYER met3 ;
        RECT 0.000 204.040 4.000 204.640 ;
    END
  END read_data[16]
  PIN read_data[17]
    DIRECTION OUTPUT TRISTATE ;
    USE SIGNAL ;
    ANTENNADIFFAREA 0.795200 ;
    PORT
      LAYER met3 ;
        RECT 0.000 1696.640 4.000 1697.240 ;
    END
  END read_data[17]
  PIN read_data[18]
    DIRECTION OUTPUT TRISTATE ;
    USE SIGNAL ;
    ANTENNADIFFAREA 0.795200 ;
    PORT
      LAYER met2 ;
        RECT 483.090 1796.000 483.370 1800.000 ;
    END
  END read_data[18]
  PIN read_data[19]
    DIRECTION OUTPUT TRISTATE ;
    USE SIGNAL ;
    ANTENNADIFFAREA 0.795200 ;
    PORT
      LAYER met2 ;
        RECT 1069.130 1796.000 1069.410 1800.000 ;
    END
  END read_data[19]
  PIN read_data[1]
    DIRECTION OUTPUT TRISTATE ;
    USE SIGNAL ;
    ANTENNADIFFAREA 0.795200 ;
    PORT
      LAYER met3 ;
        RECT 0.000 1336.240 4.000 1336.840 ;
    END
  END read_data[1]
  PIN read_data[20]
    DIRECTION OUTPUT TRISTATE ;
    USE SIGNAL ;
    ANTENNADIFFAREA 0.795200 ;
    PORT
      LAYER met2 ;
        RECT 289.890 0.000 290.170 4.000 ;
    END
  END read_data[20]
  PIN read_data[21]
    DIRECTION OUTPUT TRISTATE ;
    USE SIGNAL ;
    ANTENNADIFFAREA 0.795200 ;
    PORT
      LAYER met2 ;
        RECT 96.690 0.000 96.970 4.000 ;
    END
  END read_data[21]
  PIN read_data[22]
    DIRECTION OUTPUT TRISTATE ;
    USE SIGNAL ;
    ANTENNADIFFAREA 0.795200 ;
    PORT
      LAYER met3 ;
        RECT 0.000 408.040 4.000 408.640 ;
    END
  END read_data[22]
  PIN read_data[23]
    DIRECTION OUTPUT TRISTATE ;
    USE SIGNAL ;
    ANTENNADIFFAREA 0.795200 ;
    PORT
      LAYER met2 ;
        RECT 969.310 1796.000 969.590 1800.000 ;
    END
  END read_data[23]
  PIN read_data[24]
    DIRECTION OUTPUT TRISTATE ;
    USE SIGNAL ;
    ANTENNADIFFAREA 0.795200 ;
    PORT
      LAYER met2 ;
        RECT 875.930 0.000 876.210 4.000 ;
    END
  END read_data[24]
  PIN read_data[25]
    DIRECTION OUTPUT TRISTATE ;
    USE SIGNAL ;
    ANTENNADIFFAREA 0.795200 ;
    PORT
      LAYER met2 ;
        RECT 1603.650 1796.000 1603.930 1800.000 ;
    END
  END read_data[25]
  PIN read_data[26]
    DIRECTION OUTPUT TRISTATE ;
    USE SIGNAL ;
    ANTENNADIFFAREA 0.795200 ;
    PORT
      LAYER met3 ;
        RECT 1796.000 309.440 1800.000 310.040 ;
    END
  END read_data[26]
  PIN read_data[27]
    DIRECTION OUTPUT TRISTATE ;
    USE SIGNAL ;
    ANTENNADIFFAREA 0.795200 ;
    PORT
      LAYER met3 ;
        RECT 0.000 1642.240 4.000 1642.840 ;
    END
  END read_data[27]
  PIN read_data[28]
    DIRECTION OUTPUT TRISTATE ;
    USE SIGNAL ;
    ANTENNADIFFAREA 0.795200 ;
    PORT
      LAYER met3 ;
        RECT 0.000 513.440 4.000 514.040 ;
    END
  END read_data[28]
  PIN read_data[29]
    DIRECTION OUTPUT TRISTATE ;
    USE SIGNAL ;
    ANTENNADIFFAREA 0.795200 ;
    PORT
      LAYER met2 ;
        RECT 338.190 0.000 338.470 4.000 ;
    END
  END read_data[29]
  PIN read_data[2]
    DIRECTION OUTPUT TRISTATE ;
    USE SIGNAL ;
    ANTENNADIFFAREA 0.795200 ;
    PORT
      LAYER met2 ;
        RECT 631.210 0.000 631.490 4.000 ;
    END
  END read_data[2]
  PIN read_data[30]
    DIRECTION OUTPUT TRISTATE ;
    USE SIGNAL ;
    ANTENNADIFFAREA 0.795200 ;
    PORT
      LAYER met2 ;
        RECT 972.530 0.000 972.810 4.000 ;
    END
  END read_data[30]
  PIN read_data[31]
    DIRECTION OUTPUT TRISTATE ;
    USE SIGNAL ;
    ANTENNADIFFAREA 0.795200 ;
    PORT
      LAYER met3 ;
        RECT 1796.000 1183.240 1800.000 1183.840 ;
    END
  END read_data[31]
  PIN read_data[3]
    DIRECTION OUTPUT TRISTATE ;
    USE SIGNAL ;
    ANTENNADIFFAREA 0.795200 ;
    PORT
      LAYER met2 ;
        RECT 1020.830 0.000 1021.110 4.000 ;
    END
  END read_data[3]
  PIN read_data[4]
    DIRECTION OUTPUT TRISTATE ;
    USE SIGNAL ;
    ANTENNADIFFAREA 0.795200 ;
    PORT
      LAYER met2 ;
        RECT 1358.930 1796.000 1359.210 1800.000 ;
    END
  END read_data[4]
  PIN read_data[5]
    DIRECTION OUTPUT TRISTATE ;
    USE SIGNAL ;
    ANTENNADIFFAREA 0.795200 ;
    PORT
      LAYER met2 ;
        RECT 1310.630 1796.000 1310.910 1800.000 ;
    END
  END read_data[5]
  PIN read_data[6]
    DIRECTION OUTPUT TRISTATE ;
    USE SIGNAL ;
    ANTENNADIFFAREA 0.795200 ;
    PORT
      LAYER met2 ;
        RECT 45.170 1796.000 45.450 1800.000 ;
    END
  END read_data[6]
  PIN read_data[7]
    DIRECTION OUTPUT TRISTATE ;
    USE SIGNAL ;
    ANTENNADIFFAREA 0.795200 ;
    PORT
      LAYER met2 ;
        RECT 338.190 1796.000 338.470 1800.000 ;
    END
  END read_data[7]
  PIN read_data[8]
    DIRECTION OUTPUT TRISTATE ;
    USE SIGNAL ;
    ANTENNADIFFAREA 0.795200 ;
    PORT
      LAYER met2 ;
        RECT 1217.250 0.000 1217.530 4.000 ;
    END
  END read_data[8]
  PIN read_data[9]
    DIRECTION OUTPUT TRISTATE ;
    USE SIGNAL ;
    ANTENNADIFFAREA 0.795200 ;
    PORT
      LAYER met3 ;
        RECT 0.000 462.440 4.000 463.040 ;
    END
  END read_data[9]
  PIN rst_n
    DIRECTION INPUT ;
    USE SIGNAL ;
    ANTENNAGATEAREA 0.560700 ;
    ANTENNADIFFAREA 0.434700 ;
    PORT
      LAYER met3 ;
        RECT 0.000 1591.240 4.000 1591.840 ;
    END
  END rst_n
  PIN start
    DIRECTION INPUT ;
    USE SIGNAL ;
    ANTENNAGATEAREA 1.864800 ;
    ANTENNADIFFAREA 1.738800 ;
    PORT
      LAYER met3 ;
        RECT 1796.000 822.840 1800.000 823.440 ;
    END
  END start
  OBS
      LAYER li1 ;
        RECT 20.240 21.675 1779.740 1778.965 ;
      LAYER met1 ;
        RECT 0.070 13.980 1797.150 1779.120 ;
      LAYER met2 ;
        RECT 0.100 1795.720 44.890 1799.125 ;
        RECT 45.730 1795.720 93.190 1799.125 ;
        RECT 94.030 1795.720 141.490 1799.125 ;
        RECT 142.330 1795.720 189.790 1799.125 ;
        RECT 190.630 1795.720 238.090 1799.125 ;
        RECT 238.930 1795.720 289.610 1799.125 ;
        RECT 290.450 1795.720 337.910 1799.125 ;
        RECT 338.750 1795.720 386.210 1799.125 ;
        RECT 387.050 1795.720 434.510 1799.125 ;
        RECT 435.350 1795.720 482.810 1799.125 ;
        RECT 483.650 1795.720 531.110 1799.125 ;
        RECT 531.950 1795.720 579.410 1799.125 ;
        RECT 580.250 1795.720 627.710 1799.125 ;
        RECT 628.550 1795.720 679.230 1799.125 ;
        RECT 680.070 1795.720 727.530 1799.125 ;
        RECT 728.370 1795.720 775.830 1799.125 ;
        RECT 776.670 1795.720 824.130 1799.125 ;
        RECT 824.970 1795.720 872.430 1799.125 ;
        RECT 873.270 1795.720 920.730 1799.125 ;
        RECT 921.570 1795.720 969.030 1799.125 ;
        RECT 969.870 1795.720 1017.330 1799.125 ;
        RECT 1018.170 1795.720 1068.850 1799.125 ;
        RECT 1069.690 1795.720 1117.150 1799.125 ;
        RECT 1117.990 1795.720 1165.450 1799.125 ;
        RECT 1166.290 1795.720 1213.750 1799.125 ;
        RECT 1214.590 1795.720 1262.050 1799.125 ;
        RECT 1262.890 1795.720 1310.350 1799.125 ;
        RECT 1311.190 1795.720 1358.650 1799.125 ;
        RECT 1359.490 1795.720 1406.950 1799.125 ;
        RECT 1407.790 1795.720 1458.470 1799.125 ;
        RECT 1459.310 1795.720 1506.770 1799.125 ;
        RECT 1507.610 1795.720 1555.070 1799.125 ;
        RECT 1555.910 1795.720 1603.370 1799.125 ;
        RECT 1604.210 1795.720 1651.670 1799.125 ;
        RECT 1652.510 1795.720 1699.970 1799.125 ;
        RECT 1700.810 1795.720 1748.270 1799.125 ;
        RECT 1749.110 1795.720 1796.570 1799.125 ;
        RECT 0.100 4.280 1797.120 1795.720 ;
        RECT 0.650 0.155 48.110 4.280 ;
        RECT 48.950 0.155 96.410 4.280 ;
        RECT 97.250 0.155 144.710 4.280 ;
        RECT 145.550 0.155 193.010 4.280 ;
        RECT 193.850 0.155 241.310 4.280 ;
        RECT 242.150 0.155 289.610 4.280 ;
        RECT 290.450 0.155 337.910 4.280 ;
        RECT 338.750 0.155 389.430 4.280 ;
        RECT 390.270 0.155 437.730 4.280 ;
        RECT 438.570 0.155 486.030 4.280 ;
        RECT 486.870 0.155 534.330 4.280 ;
        RECT 535.170 0.155 582.630 4.280 ;
        RECT 583.470 0.155 630.930 4.280 ;
        RECT 631.770 0.155 679.230 4.280 ;
        RECT 680.070 0.155 727.530 4.280 ;
        RECT 728.370 0.155 779.050 4.280 ;
        RECT 779.890 0.155 827.350 4.280 ;
        RECT 828.190 0.155 875.650 4.280 ;
        RECT 876.490 0.155 923.950 4.280 ;
        RECT 924.790 0.155 972.250 4.280 ;
        RECT 973.090 0.155 1020.550 4.280 ;
        RECT 1021.390 0.155 1068.850 4.280 ;
        RECT 1069.690 0.155 1117.150 4.280 ;
        RECT 1117.990 0.155 1168.670 4.280 ;
        RECT 1169.510 0.155 1216.970 4.280 ;
        RECT 1217.810 0.155 1265.270 4.280 ;
        RECT 1266.110 0.155 1313.570 4.280 ;
        RECT 1314.410 0.155 1361.870 4.280 ;
        RECT 1362.710 0.155 1410.170 4.280 ;
        RECT 1411.010 0.155 1458.470 4.280 ;
        RECT 1459.310 0.155 1506.770 4.280 ;
        RECT 1507.610 0.155 1558.290 4.280 ;
        RECT 1559.130 0.155 1606.590 4.280 ;
        RECT 1607.430 0.155 1654.890 4.280 ;
        RECT 1655.730 0.155 1703.190 4.280 ;
        RECT 1704.030 0.155 1751.490 4.280 ;
        RECT 1752.330 0.155 1797.120 4.280 ;
      LAYER met3 ;
        RECT 4.400 1798.240 1796.000 1799.105 ;
        RECT 4.000 1748.640 1796.000 1798.240 ;
        RECT 4.400 1747.240 1795.600 1748.640 ;
        RECT 4.000 1697.640 1796.000 1747.240 ;
        RECT 4.400 1696.240 1795.600 1697.640 ;
        RECT 4.000 1646.640 1796.000 1696.240 ;
        RECT 4.000 1645.240 1795.600 1646.640 ;
        RECT 4.000 1643.240 1796.000 1645.240 ;
        RECT 4.400 1641.840 1796.000 1643.240 ;
        RECT 4.000 1595.640 1796.000 1641.840 ;
        RECT 4.000 1594.240 1795.600 1595.640 ;
        RECT 4.000 1592.240 1796.000 1594.240 ;
        RECT 4.400 1590.840 1796.000 1592.240 ;
        RECT 4.000 1544.640 1796.000 1590.840 ;
        RECT 4.000 1543.240 1795.600 1544.640 ;
        RECT 4.000 1541.240 1796.000 1543.240 ;
        RECT 4.400 1539.840 1796.000 1541.240 ;
        RECT 4.000 1493.640 1796.000 1539.840 ;
        RECT 4.000 1492.240 1795.600 1493.640 ;
        RECT 4.000 1490.240 1796.000 1492.240 ;
        RECT 4.400 1488.840 1796.000 1490.240 ;
        RECT 4.000 1442.640 1796.000 1488.840 ;
        RECT 4.000 1441.240 1795.600 1442.640 ;
        RECT 4.000 1439.240 1796.000 1441.240 ;
        RECT 4.400 1437.840 1796.000 1439.240 ;
        RECT 4.000 1391.640 1796.000 1437.840 ;
        RECT 4.000 1390.240 1795.600 1391.640 ;
        RECT 4.000 1388.240 1796.000 1390.240 ;
        RECT 4.400 1386.840 1796.000 1388.240 ;
        RECT 4.000 1337.240 1796.000 1386.840 ;
        RECT 4.400 1335.840 1795.600 1337.240 ;
        RECT 4.000 1286.240 1796.000 1335.840 ;
        RECT 4.400 1284.840 1795.600 1286.240 ;
        RECT 4.000 1235.240 1796.000 1284.840 ;
        RECT 4.000 1233.840 1795.600 1235.240 ;
        RECT 4.000 1231.840 1796.000 1233.840 ;
        RECT 4.400 1230.440 1796.000 1231.840 ;
        RECT 4.000 1184.240 1796.000 1230.440 ;
        RECT 4.000 1182.840 1795.600 1184.240 ;
        RECT 4.000 1180.840 1796.000 1182.840 ;
        RECT 4.400 1179.440 1796.000 1180.840 ;
        RECT 4.000 1133.240 1796.000 1179.440 ;
        RECT 4.000 1131.840 1795.600 1133.240 ;
        RECT 4.000 1129.840 1796.000 1131.840 ;
        RECT 4.400 1128.440 1796.000 1129.840 ;
        RECT 4.000 1082.240 1796.000 1128.440 ;
        RECT 4.000 1080.840 1795.600 1082.240 ;
        RECT 4.000 1078.840 1796.000 1080.840 ;
        RECT 4.400 1077.440 1796.000 1078.840 ;
        RECT 4.000 1031.240 1796.000 1077.440 ;
        RECT 4.000 1029.840 1795.600 1031.240 ;
        RECT 4.000 1027.840 1796.000 1029.840 ;
        RECT 4.400 1026.440 1796.000 1027.840 ;
        RECT 4.000 980.240 1796.000 1026.440 ;
        RECT 4.000 978.840 1795.600 980.240 ;
        RECT 4.000 976.840 1796.000 978.840 ;
        RECT 4.400 975.440 1796.000 976.840 ;
        RECT 4.000 925.840 1796.000 975.440 ;
        RECT 4.400 924.440 1795.600 925.840 ;
        RECT 4.000 874.840 1796.000 924.440 ;
        RECT 4.400 873.440 1795.600 874.840 ;
        RECT 4.000 823.840 1796.000 873.440 ;
        RECT 4.000 822.440 1795.600 823.840 ;
        RECT 4.000 820.440 1796.000 822.440 ;
        RECT 4.400 819.040 1796.000 820.440 ;
        RECT 4.000 772.840 1796.000 819.040 ;
        RECT 4.000 771.440 1795.600 772.840 ;
        RECT 4.000 769.440 1796.000 771.440 ;
        RECT 4.400 768.040 1796.000 769.440 ;
        RECT 4.000 721.840 1796.000 768.040 ;
        RECT 4.000 720.440 1795.600 721.840 ;
        RECT 4.000 718.440 1796.000 720.440 ;
        RECT 4.400 717.040 1796.000 718.440 ;
        RECT 4.000 670.840 1796.000 717.040 ;
        RECT 4.000 669.440 1795.600 670.840 ;
        RECT 4.000 667.440 1796.000 669.440 ;
        RECT 4.400 666.040 1796.000 667.440 ;
        RECT 4.000 619.840 1796.000 666.040 ;
        RECT 4.000 618.440 1795.600 619.840 ;
        RECT 4.000 616.440 1796.000 618.440 ;
        RECT 4.400 615.040 1796.000 616.440 ;
        RECT 4.000 568.840 1796.000 615.040 ;
        RECT 4.000 567.440 1795.600 568.840 ;
        RECT 4.000 565.440 1796.000 567.440 ;
        RECT 4.400 564.040 1796.000 565.440 ;
        RECT 4.000 514.440 1796.000 564.040 ;
        RECT 4.400 513.040 1795.600 514.440 ;
        RECT 4.000 463.440 1796.000 513.040 ;
        RECT 4.400 462.040 1795.600 463.440 ;
        RECT 4.000 412.440 1796.000 462.040 ;
        RECT 4.000 411.040 1795.600 412.440 ;
        RECT 4.000 409.040 1796.000 411.040 ;
        RECT 4.400 407.640 1796.000 409.040 ;
        RECT 4.000 361.440 1796.000 407.640 ;
        RECT 4.000 360.040 1795.600 361.440 ;
        RECT 4.000 358.040 1796.000 360.040 ;
        RECT 4.400 356.640 1796.000 358.040 ;
        RECT 4.000 310.440 1796.000 356.640 ;
        RECT 4.000 309.040 1795.600 310.440 ;
        RECT 4.000 307.040 1796.000 309.040 ;
        RECT 4.400 305.640 1796.000 307.040 ;
        RECT 4.000 259.440 1796.000 305.640 ;
        RECT 4.000 258.040 1795.600 259.440 ;
        RECT 4.000 256.040 1796.000 258.040 ;
        RECT 4.400 254.640 1796.000 256.040 ;
        RECT 4.000 208.440 1796.000 254.640 ;
        RECT 4.000 207.040 1795.600 208.440 ;
        RECT 4.000 205.040 1796.000 207.040 ;
        RECT 4.400 203.640 1796.000 205.040 ;
        RECT 4.000 157.440 1796.000 203.640 ;
        RECT 4.000 156.040 1795.600 157.440 ;
        RECT 4.000 154.040 1796.000 156.040 ;
        RECT 4.400 152.640 1796.000 154.040 ;
        RECT 4.000 103.040 1796.000 152.640 ;
        RECT 4.400 101.640 1795.600 103.040 ;
        RECT 4.000 52.040 1796.000 101.640 ;
        RECT 4.400 50.640 1795.600 52.040 ;
        RECT 4.000 1.040 1796.000 50.640 ;
        RECT 4.000 0.175 1795.600 1.040 ;
      LAYER met4 ;
        RECT 66.110 487.080 188.960 1778.025 ;
        RECT 191.360 487.080 192.260 1778.025 ;
        RECT 194.660 1107.080 342.560 1778.025 ;
        RECT 344.960 1107.080 345.860 1778.025 ;
        RECT 348.260 1107.080 496.160 1778.025 ;
        RECT 498.560 1107.080 499.460 1778.025 ;
        RECT 501.860 1107.080 649.760 1778.025 ;
        RECT 652.160 1107.700 653.060 1778.025 ;
        RECT 655.460 1107.700 803.360 1778.025 ;
        RECT 652.160 1107.080 803.360 1107.700 ;
        RECT 805.760 1107.080 806.660 1778.025 ;
        RECT 809.060 1113.120 956.960 1778.025 ;
        RECT 809.060 1107.080 856.700 1113.120 ;
        RECT 194.660 690.420 856.700 1107.080 ;
        RECT 194.660 487.080 342.560 690.420 ;
        RECT 344.960 487.080 345.860 690.420 ;
        RECT 348.260 689.800 499.460 690.420 ;
        RECT 348.260 487.080 496.160 689.800 ;
        RECT 498.560 487.080 499.460 689.800 ;
        RECT 501.860 536.040 649.760 690.420 ;
        RECT 652.160 689.800 803.360 690.420 ;
        RECT 652.160 536.040 653.060 689.800 ;
        RECT 655.460 536.660 803.360 689.800 ;
        RECT 805.760 536.660 806.660 690.420 ;
        RECT 655.460 536.040 806.660 536.660 ;
        RECT 809.060 684.800 856.700 690.420 ;
        RECT 859.100 684.800 860.380 1113.120 ;
        RECT 862.780 1107.080 956.960 1113.120 ;
        RECT 959.360 1107.080 960.260 1778.025 ;
        RECT 962.660 1107.700 1110.560 1778.025 ;
        RECT 1112.960 1107.700 1113.860 1778.025 ;
        RECT 962.660 1107.080 1113.860 1107.700 ;
        RECT 1116.260 1107.080 1264.160 1778.025 ;
        RECT 1266.560 1107.080 1267.460 1778.025 ;
        RECT 1269.860 1107.080 1417.760 1778.025 ;
        RECT 862.780 690.420 1417.760 1107.080 ;
        RECT 862.780 684.800 956.960 690.420 ;
        RECT 809.060 536.040 956.960 684.800 ;
        RECT 959.360 536.040 960.260 690.420 ;
        RECT 962.660 536.040 1110.560 690.420 ;
        RECT 1112.960 689.800 1264.160 690.420 ;
        RECT 1112.960 536.040 1113.860 689.800 ;
        RECT 1116.260 536.040 1264.160 689.800 ;
        RECT 501.860 492.960 1264.160 536.040 ;
        RECT 501.860 487.080 601.860 492.960 ;
        RECT 66.110 70.420 601.860 487.080 ;
        RECT 66.110 22.615 188.960 70.420 ;
        RECT 191.360 69.800 496.160 70.420 ;
        RECT 191.360 22.615 192.260 69.800 ;
        RECT 194.660 22.615 342.560 69.800 ;
        RECT 344.960 22.615 345.860 69.800 ;
        RECT 348.260 22.615 496.160 69.800 ;
        RECT 498.560 22.615 499.460 70.420 ;
        RECT 501.860 64.640 601.860 70.420 ;
        RECT 604.260 64.640 605.540 492.960 ;
        RECT 607.940 70.420 1159.380 492.960 ;
        RECT 607.940 64.640 649.760 70.420 ;
        RECT 501.860 22.615 649.760 64.640 ;
        RECT 652.160 22.615 653.060 70.420 ;
        RECT 655.460 22.615 803.360 70.420 ;
        RECT 805.760 22.615 806.660 70.420 ;
        RECT 809.060 22.615 956.960 70.420 ;
        RECT 959.360 22.615 960.260 70.420 ;
        RECT 962.660 22.615 1110.560 70.420 ;
        RECT 1112.960 22.615 1113.860 70.420 ;
        RECT 1116.260 64.640 1159.380 70.420 ;
        RECT 1161.780 64.640 1163.060 492.960 ;
        RECT 1165.460 487.080 1264.160 492.960 ;
        RECT 1266.560 487.080 1267.460 690.420 ;
        RECT 1269.860 487.080 1417.760 690.420 ;
        RECT 1420.160 487.700 1421.060 1778.025 ;
        RECT 1423.460 487.700 1571.360 1778.025 ;
        RECT 1420.160 487.080 1571.360 487.700 ;
        RECT 1573.760 487.080 1574.660 1778.025 ;
        RECT 1577.060 487.080 1724.960 1778.025 ;
        RECT 1165.460 70.420 1724.960 487.080 ;
        RECT 1165.460 64.640 1264.160 70.420 ;
        RECT 1116.260 22.615 1264.160 64.640 ;
        RECT 1266.560 22.615 1267.460 70.420 ;
        RECT 1269.860 22.615 1417.760 70.420 ;
        RECT 1420.160 69.800 1571.360 70.420 ;
        RECT 1420.160 22.615 1421.060 69.800 ;
        RECT 1423.460 22.615 1571.360 69.800 ;
        RECT 1573.760 22.615 1574.660 70.420 ;
        RECT 1577.060 22.615 1724.960 70.420 ;
        RECT 1727.360 22.615 1728.260 1778.025 ;
        RECT 1730.660 22.615 1762.850 1778.025 ;
      LAYER met5 ;
        RECT 65.900 656.830 1763.060 699.500 ;
        RECT 65.900 503.650 1763.060 648.730 ;
        RECT 65.900 350.470 1763.060 495.550 ;
        RECT 65.900 197.290 1763.060 342.370 ;
        RECT 65.900 58.700 1763.060 189.190 ;
  END
END ntt_core_256_sram
END LIBRARY

